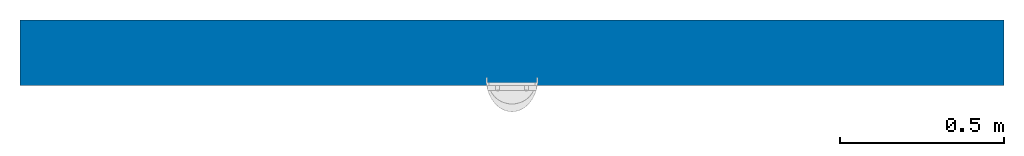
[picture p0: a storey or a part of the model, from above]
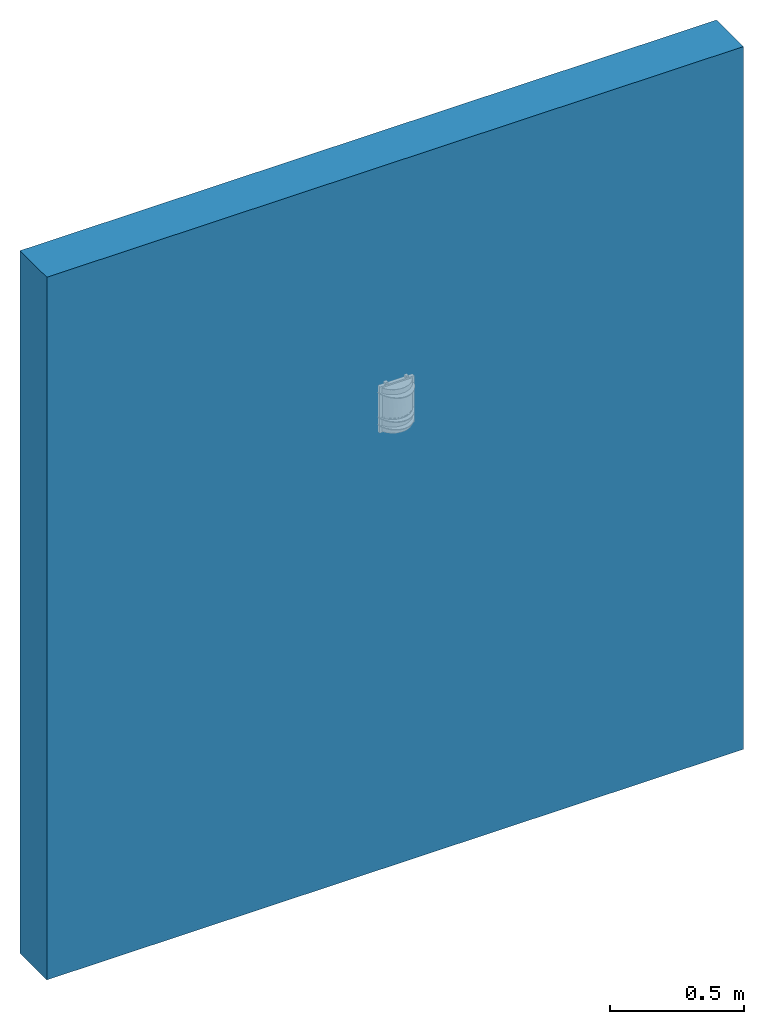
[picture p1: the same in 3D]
Properties of the parts of a building model (IFC2X3)

# File
Description: ViewDefinition [CoordinationView_V2.0], RevitIdentifiers [ContentGUID: 1f98d6a2-4275-4335-88fd-805577486c03, VersionGUID: 9af4c5f3-726d-4a3e-8a5f-880eae424b84, NumberOfSaves: 0], CoordinateReference [CoordinateBase: Shared Coordinates]
File name: 8-cargo-wall-light.ifc
Time: 2026-02-08T19:02:31+03:30
Written by: ODA SDAI 24.12
Made in: Autodesk Revit 25.4.0.32 (ENU) - IFC 25.4.0.32

# IfcProject, Project Number
LongName: home desing; Phase: Project Status

# IfcSite, Default
RefLatitude: 42, 21, 30, 344238; RefLongitude: -71, -3, -35, -194702; RefElevation: 0 m

# IfcBuilding
Pset_BuildingCommon - NumberOfStoreys: 1

# IfcBuildingStorey: Level:8mm Head (5)
Pset_AirSideSystemInformation - sets with these values: 2
Name | LongName = Name | Elevation (m)
Level 1 | Level 1 | 0
Level 2 | Level 2 | 3.2
Level 3 | Level 3 | 6.4
Level 4 | Level 4 | 9.6
Level 5 | Level 5 | 12.8

# IfcBuildingElementProxy: Screw:Screw (2)
In: Level 1
Type - Material: Brass
Pset_BuildingElementProxyCommon - Reference: Screw; sets with these values: 2
Name (Screw:Screw:...)
204086
204087

# IfcDistributionPort, Port_204083_1
Description: Flow; FlowDirection: SOURCEANDSINK

# IfcFlowTerminal: 8-cargo-wall-light:Variant 1 - Raw Brass, 8-cargo-wall-light:Variant 1 - Raw Brass:204083
In: Level 1
Type - Material: Brass, Mat-Glass
Type - Pset_ManufacturerTypeInformation - Manufacturer: Lampfix
Pset_DistributionFlowElementCommon - Reference: Variant 1 - Raw Brass; sets with these values: 2

# IfcOpeningElement: Opening (2)
In: Level 1
Pset_OpeningElementCommon - Reference: Variant 1 - Raw Brass; sets with these values: 2

# IfcWallStandardCase: Basic Wall:Wall 20cm2, Basic Wall:Wall 20cm2:202100
In: Level 1
Type - PredefinedType: STANDARD; Material: Default Wall 0.2 m
Pset_QuantityTakeOff - Reference: Wall 20cm2; sets with these values: 2
Pset_WallCommon - Reference: Wall 20cm2; IsExternal: yes; ExtendToStructure: no; LoadBearing: no
